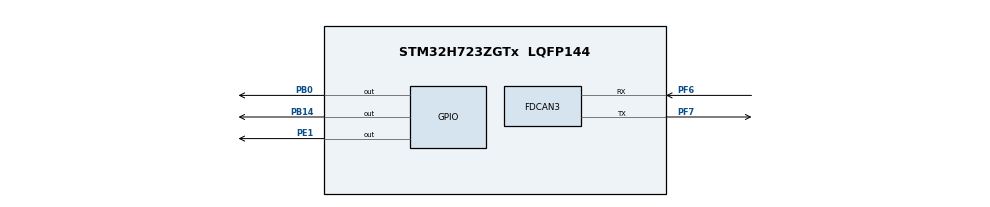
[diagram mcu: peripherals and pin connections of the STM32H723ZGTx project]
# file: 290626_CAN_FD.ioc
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CORTEX_M7.default_mode_Activation=1
FDCAN3.CalculateBaudRateNominal=500000
FDCAN3.CalculateTimeBitNominal=2000
FDCAN3.CalculateTimeQuantumNominal=125.0
FDCAN3.NominalPrescaler=5
FDCAN3.NominalTimeSeg1=12
FDCAN3.NominalTimeSeg2=3
Mcu.Family=STM32H7
Mcu.Name=STM32H723ZGTx
Mcu.Package=LQFP144
NUCLEO-H723ZG.LD2=false
NVIC.FDCAN3_IT0_IRQn=true\:0\:0\:false\:false\:true\:true\:true\:true
NVIC.FDCAN3_IT1_IRQn=true\:0\:0\:false\:false\:true\:true\:true\:true
NVIC.PriorityGroup=NVIC_PRIORITYGROUP_4
PA13(JTMS/SWDIO).GPIO_Label=SWDIO
PA13(JTMS/SWDIO).Signal=DEBUG_JTMS-SWDIO
PA14(JTCK/SWCLK).GPIO_Label=SWCLK
PA14(JTCK/SWCLK).Signal=DEBUG_JTCK-SWCLK
PB0.Signal=GPIO_Output
PB14.Signal=GPIO_Output
PC14-OSC32_IN.Signal=RCC_OSC32_IN
PC15-OSC32_OUT.Signal=RCC_OSC32_OUT
PD8.GPIO_Label=STLK_VCP_RX
PD8.Signal=USART3_TX
PD9.GPIO_Label=STLK_VCP_TX
PD9.Signal=USART3_RX
PE1.Signal=GPIO_Output
PF6.Mode=FDCAN_Activate
PF6.Signal=FDCAN3_RX
PF7.Mode=FDCAN_Activate
PF7.Signal=FDCAN3_TX
ProjectManager.HeapSize=0x200
ProjectManager.StackSize=0x400
ProjectManager.TargetToolchain=STM32CubeIDE
RCC.ADCFreq_Value=152000000
RCC.APB1Freq_Value=60000000
RCC.APB2Freq_Value=60000000
RCC.APB3Freq_Value=60000000
RCC.APB4Freq_Value=60000000
RCC.CortexFreq_Value=240000000
RCC.D1PPRE=RCC_APB3_DIV2
RCC.D2PPRE1=RCC_APB1_DIV2
RCC.D2PPRE2=RCC_APB2_DIV2
RCC.D3PPRE=RCC_APB4_DIV2
RCC.DIVM1=4
RCC.DIVM2=1
RCC.DIVN1=60
RCC.DIVN2=19
RCC.DIVP1=1
RCC.DIVQ1=6
RCC.HCLKFreq_Value=120000000
RCC.HPRE=RCC_HCLK_DIV2
RCC.HSE_VALUE=8000000
RCC.HSIDiv=RCC_PLLSAIDIVR_4
RCC.PLLFRACN=0
RCC.SYSCLKFreq_VALUE=240000000
RCC.SYSCLKSource=RCC_SYSCLKSOURCE_PLLCLK
RCC.USBCLockSelection=RCC_USBCLKSOURCE_HSI48
RCC.USBFreq_Value=48000000
VP_MEMORYMAP_VS_MEMORYMAP.Mode=CurAppReg
VP_NUCLEO-H723ZG_VS_BSP_COMMON.Mode=COMMON
board=NUCLEO-H723ZG

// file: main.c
/* USER CODE BEGIN Header */
/**
  ******************************************************************************
  * @file           : main.c
  * @brief          : Main program body
  ******************************************************************************
  * @attention
  *
  * Copyright (c) 2026 STMicroelectronics.
  * All rights reserved.
  *
  * This software is licensed under terms that can be found in the LICENSE file
  * in the root directory of this software component.
  * If no LICENSE file comes with this software, it is provided AS-IS.
  *
  ******************************************************************************
  */
/* USER CODE END Header */
#include "main.h"

FDCAN_HandleTypeDef hfdcan3;

/* USER CODE BEGIN PV */
uint8_t error_status =0;
FDCAN_RxHeaderTypeDef RxHeader;
uint8_t RxData[64];
/* USER CODE END PV */

void SystemClock_Config(void);
static void MPU_Config(void);
static void MX_GPIO_Init(void);
static void MX_FDCAN3_Init(void);
/* USER CODE BEGIN PFP */
void Send_CANFD_Message(void);
void Configure_FDCAN3_Filter(void);
void Check_For_Incoming_Messages(void);
/* USER CODE END PFP */

int main(void)
{

  /* MPU Configuration--------------------------------------------------------*/
  MPU_Config();

  /* MCU Configuration--------------------------------------------------------*/

  /* Reset of all peripherals, Initializes the Flash interface and the Systick. */
  HAL_Init();

  /* Configure the system clock */
  SystemClock_Config();

  /* Initialize all configured peripherals */
  MX_GPIO_Init();
  MX_FDCAN3_Init();
  Configure_FDCAN3_Filter();

  /* USER CODE BEGIN 2 */
  if (HAL_FDCAN_Start(&hfdcan3) != HAL_OK)
  {
	  Error_Handler();
  }

  uint32_t last_tx_tick = 0;
  /* USER CODE END 2 */

  /* Infinite loop */
  /* USER CODE BEGIN WHILE */
  while (1)
  {
	  Check_For_Incoming_Messages();

	  if (HAL_GetTick() - last_tx_tick >= 1000)
	  {
		  Send_CANFD_Message();
		  last_tx_tick = HAL_GetTick();
	  }
	  if (RxData[0] == 1){
	      HAL_GPIO_WritePin(GPIOB, GPIO_PIN_0, GPIO_PIN_SET);
	  }
	  else if (RxData[0] == 0){
	  	  HAL_GPIO_WritePin(GPIOB, GPIO_PIN_0, GPIO_PIN_RESET);
	  }
	  if (RxData[1] == 1){
	  	  HAL_GPIO_WritePin(GPIOE, GPIO_PIN_1, GPIO_PIN_SET);
	  }
	  else if (RxData[1] == 0){
	  	  HAL_GPIO_WritePin(GPIOE, GPIO_PIN_1, GPIO_PIN_RESET);
	  }
	  if (RxData[2] == 1){
	  	  HAL_GPIO_WritePin(GPIOB, GPIO_PIN_14, GPIO_PIN_SET);
	  }
	   else if (RxData[2] == 0){
	      HAL_GPIO_WritePin(GPIOB, GPIO_PIN_14, GPIO_PIN_RESET);
	  }

    /* USER CODE END WHILE */

  }
}

void SystemClock_Config(void)
{
  RCC_OscInitTypeDef RCC_OscInitStruct = {0};
  RCC_ClkInitTypeDef RCC_ClkInitStruct = {0};

  /** Supply configuration update enable
  */
  HAL_PWREx_ConfigSupply(PWR_LDO_SUPPLY);

  /** Configure the main internal regulator output voltage
  */
  __HAL_PWR_VOLTAGESCALING_CONFIG(PWR_REGULATOR_VOLTAGE_SCALE2);

  while(!__HAL_PWR_GET_FLAG(PWR_FLAG_VOSRDY)) {}

  /** Initializes the RCC Oscillators according to the specified parameters
  * in the RCC_OscInitTypeDef structure.
  */
  RCC_OscInitStruct.OscillatorType = RCC_OSCILLATORTYPE_HSI;
  RCC_OscInitStruct.HSIState = RCC_HSI_DIV4;
  RCC_OscInitStruct.HSICalibrationValue = 64;
  RCC_OscInitStruct.PLL.PLLState = RCC_PLL_ON;
  RCC_OscInitStruct.PLL.PLLSource = RCC_PLLSOURCE_HSI;
  RCC_OscInitStruct.PLL.PLLM = 4;
  RCC_OscInitStruct.PLL.PLLN = 60;
  RCC_OscInitStruct.PLL.PLLP = 1;
  RCC_OscInitStruct.PLL.PLLQ = 6;
  RCC_OscInitStruct.PLL.PLLR = 2;
  RCC_OscInitStruct.PLL.PLLRGE = RCC_PLL1VCIRANGE_2;
  RCC_OscInitStruct.PLL.PLLVCOSEL = RCC_PLL1VCOWIDE;
  RCC_OscInitStruct.PLL.PLLFRACN = 0;
  if (HAL_RCC_OscConfig(&RCC_OscInitStruct) != HAL_OK)
  {
    Error_Handler();
  }

  /** Initializes the CPU, AHB and APB buses clocks
  */
  RCC_ClkInitStruct.ClockType = RCC_CLOCKTYPE_HCLK|RCC_CLOCKTYPE_SYSCLK
                              |RCC_CLOCKTYPE_PCLK1|RCC_CLOCKTYPE_PCLK2
                              |RCC_CLOCKTYPE_D3PCLK1|RCC_CLOCKTYPE_D1PCLK1;
  RCC_ClkInitStruct.SYSCLKSource = RCC_SYSCLKSOURCE_PLLCLK;
  RCC_ClkInitStruct.SYSCLKDivider = RCC_SYSCLK_DIV1;
  RCC_ClkInitStruct.AHBCLKDivider = RCC_HCLK_DIV2;
  RCC_ClkInitStruct.APB3CLKDivider = RCC_APB3_DIV2;
  RCC_ClkInitStruct.APB1CLKDivider = RCC_APB1_DIV2;
  RCC_ClkInitStruct.APB2CLKDivider = RCC_APB2_DIV2;
  RCC_ClkInitStruct.APB4CLKDivider = RCC_APB4_DIV2;

  if (HAL_RCC_ClockConfig(&RCC_ClkInitStruct, FLASH_LATENCY_2) != HAL_OK)
  {
    Error_Handler();
  }
}

static void MX_FDCAN3_Init(void)
{

  hfdcan3.Instance = FDCAN3;
  hfdcan3.Init.FrameFormat = FDCAN_FRAME_FD_BRS;
  hfdcan3.Init.Mode = FDCAN_MODE_NORMAL;
  hfdcan3.Init.AutoRetransmission = ENABLE;
  hfdcan3.Init.TransmitPause = DISABLE;
  hfdcan3.Init.ProtocolException = DISABLE;
  hfdcan3.Init.NominalPrescaler = 5;
  hfdcan3.Init.NominalSyncJumpWidth = 1;
  hfdcan3.Init.NominalTimeSeg1 = 12;
  hfdcan3.Init.NominalTimeSeg2 = 3;
  hfdcan3.Init.DataPrescaler = 2;
  hfdcan3.Init.DataSyncJumpWidth = 1;
  hfdcan3.Init.DataTimeSeg1 = 7;
  hfdcan3.Init.DataTimeSeg2 = 2;
  hfdcan3.Init.MessageRAMOffset = 0;
  hfdcan3.Init.StdFiltersNbr = 1;
  hfdcan3.Init.ExtFiltersNbr = 0;
  hfdcan3.Init.RxFifo0ElmtsNbr = 3;
  hfdcan3.Init.RxFifo0ElmtSize = 0;
  hfdcan3.Init.RxFifo1ElmtsNbr = 0;
  hfdcan3.Init.RxFifo1ElmtSize = FDCAN_DATA_BYTES_8;
  hfdcan3.Init.RxBuffersNbr = 0;
  hfdcan3.Init.RxBufferSize = FDCAN_DATA_BYTES_8;
  hfdcan3.Init.TxEventsNbr = 0;
  hfdcan3.Init.TxBuffersNbr = 0;
  hfdcan3.Init.TxFifoQueueElmtsNbr = 2;
  hfdcan3.Init.TxFifoQueueMode = FDCAN_TX_FIFO_OPERATION;
  hfdcan3.Init.TxElmtSize = FDCAN_DATA_BYTES_8;
  if (HAL_FDCAN_Init(&hfdcan3) != HAL_OK)
  {
    Error_Handler();
  }
}
  /* USER CODE BEGIN FDCAN3_Init 2 */
void Send_CANFD_Message(void)
{
  FDCAN_TxHeaderTypeDef TxHeader;
  uint8_t TxData[16] = {0x11, 0x22, 0x33, 0x44, 0x55, 0x66, 0x77, 0x88,
                        0x99, 0xAA, 0xBB, 0xCC, 0xDD, 0xEE, 0xFF, 0x00};

  TxHeader.Identifier = 0x1F4;
  TxHeader.IdType = FDCAN_STANDARD_ID;
  TxHeader.TxFrameType = FDCAN_DATA_FRAME;
  TxHeader.DataLength = FDCAN_DLC_BYTES_16;
  TxHeader.ErrorStateIndicator = FDCAN_ESI_ACTIVE;
  TxHeader.BitRateSwitch = FDCAN_BRS_ON;
  TxHeader.FDFormat = FDCAN_FD_CAN;
  TxHeader.TxEventFifoControl = FDCAN_NO_TX_EVENTS;
  TxHeader.MessageMarker = 0;

  if (HAL_FDCAN_AddMessageToTxFifoQ(&hfdcan3, &TxHeader, TxData) != HAL_OK)
  {
    // Handle transmission failure
	  error_status = 1;
  }

}

void Configure_FDCAN3_Filter(void)
{
  FDCAN_FilterTypeDef sFilterConfig;

  sFilterConfig.IdType = FDCAN_STANDARD_ID;
  sFilterConfig.FilterIndex = 0;
  sFilterConfig.FilterType = FDCAN_FILTER_TO_RXFIFO0;
  sFilterConfig.FilterConfig = FDCAN_FILTER_TO_RXFIFO0;
  sFilterConfig.FilterID1 = 0x200;
  sFilterConfig.FilterID2 = 0x7FF;

  if (HAL_FDCAN_ConfigFilter(&hfdcan3, &sFilterConfig) != HAL_OK)
  {
    Error_Handler();
  }
}

void Check_For_Incoming_Messages(void)
{
  if (HAL_FDCAN_GetRxFifoFillLevel(&hfdcan3, FDCAN_RX_FIFO0) > 0)
  {
    if (HAL_FDCAN_GetRxMessage(&hfdcan3, FDCAN_RX_FIFO0, &RxHeader, RxData) == HAL_OK)
    {
      if (RxHeader.Identifier == 0x200)
      {
      }
    }
  }
}

static void MX_GPIO_Init(void)
{
  GPIO_InitTypeDef GPIO_InitStruct = {0};

  /* GPIO Ports Clock Enable */
  __HAL_RCC_GPIOC_CLK_ENABLE();
  __HAL_RCC_GPIOF_CLK_ENABLE();
  __HAL_RCC_GPIOB_CLK_ENABLE();
  __HAL_RCC_GPIOD_CLK_ENABLE();
  __HAL_RCC_GPIOA_CLK_ENABLE();
  __HAL_RCC_GPIOE_CLK_ENABLE();

  /*Configure GPIO pin Output Level */
  HAL_GPIO_WritePin(GPIOB, GPIO_PIN_0|GPIO_PIN_14, GPIO_PIN_RESET);

  /*Configure GPIO pin Output Level */
  HAL_GPIO_WritePin(GPIOE, GPIO_PIN_1, GPIO_PIN_RESET);

  /*Configure GPIO pins : PB0 PB14 */
  GPIO_InitStruct.Pin = GPIO_PIN_0|GPIO_PIN_14;
  GPIO_InitStruct.Mode = GPIO_MODE_OUTPUT_PP;
  GPIO_InitStruct.Pull = GPIO_NOPULL;
  GPIO_InitStruct.Speed = GPIO_SPEED_FREQ_LOW;
  HAL_GPIO_Init(GPIOB, &GPIO_InitStruct);

  /*Configure GPIO pins : STLK_VCP_RX_Pin STLK_VCP_TX_Pin */
  GPIO_InitStruct.Pin = STLK_VCP_RX_Pin|STLK_VCP_TX_Pin;
  GPIO_InitStruct.Mode = GPIO_MODE_AF_PP;
  GPIO_InitStruct.Pull = GPIO_NOPULL;
  GPIO_InitStruct.Speed = GPIO_SPEED_FREQ_LOW;
  GPIO_InitStruct.Alternate = GPIO_AF7_USART3;
  HAL_GPIO_Init(GPIOD, &GPIO_InitStruct);

  /*Configure GPIO pin : PE1 */
  GPIO_InitStruct.Pin = GPIO_PIN_1;
  GPIO_InitStruct.Mode = GPIO_MODE_OUTPUT_PP;
  GPIO_InitStruct.Pull = GPIO_NOPULL;
  GPIO_InitStruct.Speed = GPIO_SPEED_FREQ_LOW;
  HAL_GPIO_Init(GPIOE, &GPIO_InitStruct);

}

 /* MPU Configuration */

void MPU_Config(void)
{
  MPU_Region_InitTypeDef MPU_InitStruct = {0};

  /* Disables the MPU */
  HAL_MPU_Disable();

  /** Initializes and configures the Region and the memory to be protected
  */
  MPU_InitStruct.Enable = MPU_REGION_ENABLE;
  MPU_InitStruct.Number = MPU_REGION_NUMBER0;
  MPU_InitStruct.BaseAddress = 0x0;
  MPU_InitStruct.Size = MPU_REGION_SIZE_4GB;
  MPU_InitStruct.SubRegionDisable = 0x87;
  MPU_InitStruct.TypeExtField = MPU_TEX_LEVEL0;
  MPU_InitStruct.AccessPermission = MPU_REGION_NO_ACCESS;
  MPU_InitStruct.DisableExec = MPU_INSTRUCTION_ACCESS_DISABLE;
  MPU_InitStruct.IsShareable = MPU_ACCESS_SHAREABLE;
  MPU_InitStruct.IsCacheable = MPU_ACCESS_NOT_CACHEABLE;
  MPU_InitStruct.IsBufferable = MPU_ACCESS_NOT_BUFFERABLE;

  HAL_MPU_ConfigRegion(&MPU_InitStruct);
  /* Enables the MPU */
  HAL_MPU_Enable(MPU_PRIVILEGED_DEFAULT);

}

void Error_Handler(void)
{
  __disable_irq();
  while (1)
  {
  }
}
